VERSION 5.7 ;
  NOWIREEXTENSIONATPIN ON ;
  DIVIDERCHAR "/" ;
  BUSBITCHARS "[]" ;
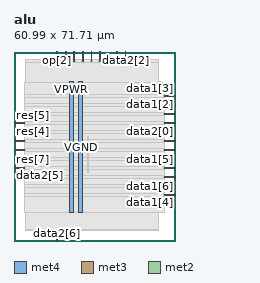
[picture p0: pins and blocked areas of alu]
MACRO alu
  CLASS BLOCK ;
  FOREIGN alu ;
  ORIGIN 0.000 0.000 ;
  SIZE 60.990 BY 71.710 ;
  PIN VGND
    DIRECTION INOUT ;
    USE GROUND ;
    PORT
      LAYER met4 ;
        RECT 24.340 10.640 25.940 60.080 ;
    END
  END VGND
  PIN VPWR
    DIRECTION INOUT ;
    USE POWER ;
    PORT
      LAYER met4 ;
        RECT 21.040 10.640 22.640 60.080 ;
    END
  END VPWR
  PIN data1[0]
    DIRECTION INPUT ;
    USE SIGNAL ;
    ANTENNAGATEAREA 0.196500 ;
    PORT
      LAYER met3 ;
        RECT 56.990 34.040 60.990 34.640 ;
    END
  END data1[0]
  PIN data1[1]
    DIRECTION INPUT ;
    USE SIGNAL ;
    ANTENNAGATEAREA 0.196500 ;
    PORT
      LAYER met3 ;
        RECT 56.990 23.840 60.990 24.440 ;
    END
  END data1[1]
  PIN data1[2]
    DIRECTION INPUT ;
    USE SIGNAL ;
    ANTENNAGATEAREA 0.196500 ;
    PORT
      LAYER met3 ;
        RECT 56.990 51.040 60.990 51.640 ;
    END
  END data1[2]
  PIN data1[3]
    DIRECTION INPUT ;
    USE SIGNAL ;
    ANTENNAGATEAREA 0.159000 ;
    PORT
      LAYER met3 ;
        RECT 56.990 54.440 60.990 55.040 ;
    END
  END data1[3]
  PIN data1[4]
    DIRECTION INPUT ;
    USE SIGNAL ;
    ANTENNAGATEAREA 0.159000 ;
    PORT
      LAYER met3 ;
        RECT 56.990 17.040 60.990 17.640 ;
    END
  END data1[4]
  PIN data1[5]
    DIRECTION INPUT ;
    USE SIGNAL ;
    ANTENNAGATEAREA 0.159000 ;
    PORT
      LAYER met3 ;
        RECT 56.990 30.640 60.990 31.240 ;
    END
  END data1[5]
  PIN data1[6]
    DIRECTION INPUT ;
    USE SIGNAL ;
    ANTENNAGATEAREA 0.196500 ;
    PORT
      LAYER met3 ;
        RECT 56.990 20.440 60.990 21.040 ;
    END
  END data1[6]
  PIN data1[7]
    DIRECTION INPUT ;
    USE SIGNAL ;
    ANTENNAGATEAREA 0.213000 ;
    PORT
      LAYER met3 ;
        RECT 56.990 27.240 60.990 27.840 ;
    END
  END data1[7]
  PIN data2[0]
    DIRECTION INPUT ;
    USE SIGNAL ;
    ANTENNAGATEAREA 0.213000 ;
    PORT
      LAYER met3 ;
        RECT 56.990 40.840 60.990 41.440 ;
    END
  END data2[0]
  PIN data2[1]
    DIRECTION INPUT ;
    USE SIGNAL ;
    ANTENNAGATEAREA 0.196500 ;
    PORT
      LAYER met3 ;
        RECT 56.990 37.440 60.990 38.040 ;
    END
  END data2[1]
  PIN data2[2]
    DIRECTION INPUT ;
    USE SIGNAL ;
    ANTENNAGATEAREA 0.196500 ;
    PORT
      LAYER met2 ;
        RECT 41.950 67.710 42.230 71.710 ;
    END
  END data2[2]
  PIN data2[3]
    DIRECTION INPUT ;
    USE SIGNAL ;
    ANTENNAGATEAREA 0.196500 ;
    PORT
      LAYER met2 ;
        RECT 29.070 67.710 29.350 71.710 ;
    END
  END data2[3]
  PIN data2[4]
    DIRECTION INPUT ;
    USE SIGNAL ;
    ANTENNAGATEAREA 0.196500 ;
    PORT
      LAYER met2 ;
        RECT 25.850 67.710 26.130 71.710 ;
    END
  END data2[4]
  PIN data2[5]
    DIRECTION INPUT ;
    USE SIGNAL ;
    ANTENNAGATEAREA 0.196500 ;
    PORT
      LAYER met3 ;
        RECT 0.000 27.240 4.000 27.840 ;
    END
  END data2[5]
  PIN data2[6]
    DIRECTION INPUT ;
    USE SIGNAL ;
    ANTENNAGATEAREA 0.196500 ;
    PORT
      LAYER met2 ;
        RECT 16.190 0.000 16.470 4.000 ;
    END
  END data2[6]
  PIN data2[7]
    DIRECTION INPUT ;
    USE SIGNAL ;
    ANTENNAGATEAREA 0.196500 ;
    PORT
      LAYER met3 ;
        RECT 0.000 23.840 4.000 24.440 ;
    END
  END data2[7]
  PIN op[0]
    DIRECTION INPUT ;
    USE SIGNAL ;
    ANTENNAGATEAREA 0.159000 ;
    PORT
      LAYER met2 ;
        RECT 22.630 67.710 22.910 71.710 ;
    END
  END op[0]
  PIN op[1]
    DIRECTION INPUT ;
    USE SIGNAL ;
    ANTENNAGATEAREA 0.159000 ;
    PORT
      LAYER met2 ;
        RECT 19.410 67.710 19.690 71.710 ;
    END
  END op[1]
  PIN op[2]
    DIRECTION INPUT ;
    USE SIGNAL ;
    ANTENNAGATEAREA 0.213000 ;
    PORT
      LAYER met2 ;
        RECT 16.190 67.710 16.470 71.710 ;
    END
  END op[2]
  PIN res[0]
    DIRECTION OUTPUT ;
    USE SIGNAL ;
    ANTENNADIFFAREA 0.445500 ;
    PORT
      LAYER met3 ;
        RECT 56.990 47.640 60.990 48.240 ;
    END
  END res[0]
  PIN res[1]
    DIRECTION OUTPUT ;
    USE SIGNAL ;
    ANTENNADIFFAREA 0.445500 ;
    PORT
      LAYER met3 ;
        RECT 56.990 44.240 60.990 44.840 ;
    END
  END res[1]
  PIN res[2]
    DIRECTION OUTPUT ;
    USE SIGNAL ;
    ANTENNADIFFAREA 0.445500 ;
    PORT
      LAYER met2 ;
        RECT 38.730 67.710 39.010 71.710 ;
    END
  END res[2]
  PIN res[3]
    DIRECTION OUTPUT ;
    USE SIGNAL ;
    ANTENNADIFFAREA 0.445500 ;
    PORT
      LAYER met2 ;
        RECT 32.290 67.710 32.570 71.710 ;
    END
  END res[3]
  PIN res[4]
    DIRECTION OUTPUT ;
    USE SIGNAL ;
    ANTENNADIFFAREA 0.445500 ;
    PORT
      LAYER met3 ;
        RECT 0.000 40.840 4.000 41.440 ;
    END
  END res[4]
  PIN res[5]
    DIRECTION OUTPUT ;
    USE SIGNAL ;
    ANTENNADIFFAREA 0.445500 ;
    PORT
      LAYER met3 ;
        RECT 0.000 44.240 4.000 44.840 ;
    END
  END res[5]
  PIN res[6]
    DIRECTION OUTPUT ;
    USE SIGNAL ;
    ANTENNADIFFAREA 0.445500 ;
    PORT
      LAYER met3 ;
        RECT 0.000 37.440 4.000 38.040 ;
    END
  END res[6]
  PIN res[7]
    DIRECTION OUTPUT ;
    USE SIGNAL ;
    ANTENNADIFFAREA 0.445500 ;
    PORT
      LAYER met3 ;
        RECT 0.000 30.640 4.000 31.240 ;
    END
  END res[7]
  PIN z
    DIRECTION OUTPUT ;
    USE SIGNAL ;
    ANTENNADIFFAREA 0.445500 ;
    PORT
      LAYER met3 ;
        RECT 0.000 34.040 4.000 34.640 ;
    END
  END z
  OBS
      LAYER nwell ;
        RECT 5.330 10.795 55.390 59.925 ;
      LAYER li1 ;
        RECT 5.520 10.795 55.200 59.925 ;
      LAYER met1 ;
        RECT 4.210 10.640 55.200 60.080 ;
      LAYER met2 ;
        RECT 4.230 67.430 15.910 68.410 ;
        RECT 16.750 67.430 19.130 68.410 ;
        RECT 19.970 67.430 22.350 68.410 ;
        RECT 23.190 67.430 25.570 68.410 ;
        RECT 26.410 67.430 28.790 68.410 ;
        RECT 29.630 67.430 32.010 68.410 ;
        RECT 32.850 67.430 38.450 68.410 ;
        RECT 39.290 67.430 41.670 68.410 ;
        RECT 42.510 67.430 54.650 68.410 ;
        RECT 4.230 4.280 54.650 67.430 ;
        RECT 4.230 4.000 15.910 4.280 ;
        RECT 16.750 4.000 54.650 4.280 ;
      LAYER met3 ;
        RECT 3.990 55.440 56.990 60.005 ;
        RECT 3.990 54.040 56.590 55.440 ;
        RECT 3.990 52.040 56.990 54.040 ;
        RECT 3.990 50.640 56.590 52.040 ;
        RECT 3.990 48.640 56.990 50.640 ;
        RECT 3.990 47.240 56.590 48.640 ;
        RECT 3.990 45.240 56.990 47.240 ;
        RECT 4.400 43.840 56.590 45.240 ;
        RECT 3.990 41.840 56.990 43.840 ;
        RECT 4.400 40.440 56.590 41.840 ;
        RECT 3.990 38.440 56.990 40.440 ;
        RECT 4.400 37.040 56.590 38.440 ;
        RECT 3.990 35.040 56.990 37.040 ;
        RECT 4.400 33.640 56.590 35.040 ;
        RECT 3.990 31.640 56.990 33.640 ;
        RECT 4.400 30.240 56.590 31.640 ;
        RECT 3.990 28.240 56.990 30.240 ;
        RECT 4.400 26.840 56.590 28.240 ;
        RECT 3.990 24.840 56.990 26.840 ;
        RECT 4.400 23.440 56.590 24.840 ;
        RECT 3.990 21.440 56.990 23.440 ;
        RECT 3.990 20.040 56.590 21.440 ;
        RECT 3.990 18.040 56.990 20.040 ;
        RECT 3.990 16.640 56.590 18.040 ;
        RECT 3.990 10.715 56.990 16.640 ;
      LAYER met4 ;
        RECT 27.895 26.015 28.225 39.265 ;
  END
END alu
END LIBRARY

